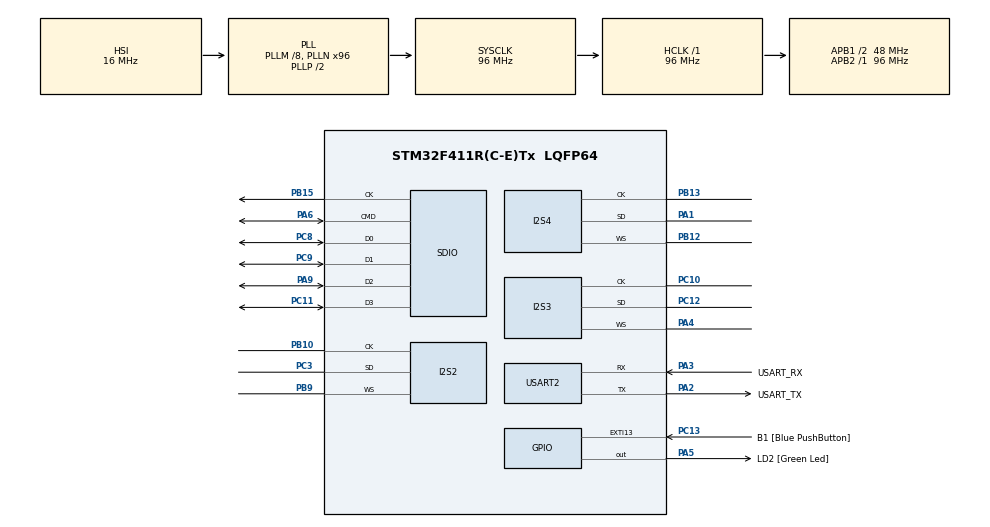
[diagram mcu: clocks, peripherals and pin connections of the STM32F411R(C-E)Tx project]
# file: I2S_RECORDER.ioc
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Dma.Request0=SPI3_RX
Dma.Request1=SPI2_RX
Dma.Request2=SPI4_RX
Dma.SPI2_RX.1.Direction=DMA_PERIPH_TO_MEMORY
Dma.SPI2_RX.1.FIFOMode=DMA_FIFOMODE_DISABLE
Dma.SPI2_RX.1.Instance=DMA1_Stream3
Dma.SPI2_RX.1.MemDataAlignment=DMA_MDATAALIGN_HALFWORD
Dma.SPI2_RX.1.MemInc=DMA_MINC_ENABLE
Dma.SPI2_RX.1.Mode=DMA_CIRCULAR
Dma.SPI2_RX.1.PeriphDataAlignment=DMA_PDATAALIGN_HALFWORD
Dma.SPI2_RX.1.PeriphInc=DMA_PINC_DISABLE
Dma.SPI2_RX.1.Priority=DMA_PRIORITY_LOW
Dma.SPI3_RX.0.Direction=DMA_PERIPH_TO_MEMORY
Dma.SPI3_RX.0.FIFOMode=DMA_FIFOMODE_DISABLE
Dma.SPI3_RX.0.Instance=DMA1_Stream0
Dma.SPI3_RX.0.MemDataAlignment=DMA_MDATAALIGN_HALFWORD
Dma.SPI3_RX.0.MemInc=DMA_MINC_ENABLE
Dma.SPI3_RX.0.Mode=DMA_CIRCULAR
Dma.SPI3_RX.0.PeriphDataAlignment=DMA_PDATAALIGN_HALFWORD
Dma.SPI3_RX.0.PeriphInc=DMA_PINC_DISABLE
Dma.SPI3_RX.0.Priority=DMA_PRIORITY_LOW
Dma.SPI4_RX.2.Direction=DMA_PERIPH_TO_MEMORY
Dma.SPI4_RX.2.FIFOMode=DMA_FIFOMODE_DISABLE
Dma.SPI4_RX.2.Instance=DMA2_Stream0
Dma.SPI4_RX.2.MemDataAlignment=DMA_MDATAALIGN_HALFWORD
Dma.SPI4_RX.2.MemInc=DMA_MINC_ENABLE
Dma.SPI4_RX.2.Mode=DMA_CIRCULAR
Dma.SPI4_RX.2.PeriphDataAlignment=DMA_PDATAALIGN_HALFWORD
Dma.SPI4_RX.2.PeriphInc=DMA_PINC_DISABLE
Dma.SPI4_RX.2.Priority=DMA_PRIORITY_LOW
FATFS._FS_LOCK=3
I2S2.AudioFreq=I2S_AUDIOFREQ_22K
I2S2.DataFormat=I2S_DATAFORMAT_16B_EXTENDED
I2S2.ErrorAudioFreq=0.26 %
I2S2.FullDuplexMode=I2S_FULLDUPLEXMODE_DISABLE
I2S2.Instance=SPI$Index
I2S2.Mode=I2S_MODE_MASTER_RX
I2S2.RealAudioFreq=22.058 KHz
I2S2.VirtualMode=I2S_MODE_MASTER
I2S3.AudioFreq=I2S_AUDIOFREQ_22K
I2S3.DataFormat=I2S_DATAFORMAT_16B_EXTENDED
I2S3.ErrorAudioFreq=0.26 %
I2S3.FullDuplexMode=I2S_FULLDUPLEXMODE_DISABLE
I2S3.Instance=SPI$Index
I2S3.Mode=I2S_MODE_MASTER_RX
I2S3.RealAudioFreq=22.058 KHz
I2S3.VirtualMode=I2S_MODE_MASTER
I2S4.AudioFreq=I2S_AUDIOFREQ_22K
I2S4.DataFormat=I2S_DATAFORMAT_16B_EXTENDED
I2S4.ErrorAudioFreq=0.26 %
I2S4.FullDuplexMode=I2S_FULLDUPLEXMODE_DISABLE
I2S4.Instance=SPI$Index
I2S4.Mode=I2S_MODE_MASTER_RX
I2S4.RealAudioFreq=22.058 KHz
I2S4.VirtualMode=I2S_MODE_MASTER
Mcu.Family=STM32F4
Mcu.Name=STM32F411R(C-E)Tx
Mcu.Package=LQFP64
NVIC.DMA1_Stream0_IRQn=true\:0\:0\:false\:false\:true\:false\:true\:true
NVIC.DMA1_Stream3_IRQn=true\:0\:0\:false\:false\:true\:false\:true\:true
NVIC.DMA2_Stream0_IRQn=true\:0\:0\:false\:false\:true\:false\:true\:true
NVIC.EXTI15_10_IRQn=true\:0\:0\:false\:false\:true\:true\:true\:true
NVIC.PriorityGroup=NVIC_PRIORITYGROUP_0
PA1.Mode=Half_Duplex_Master
PA1.Signal=I2S4_SD
PA13.GPIO_Label=TMS
PA13.Mode=Trace_Asynchronous_SW
PA13.Signal=SYS_JTMS-SWDIO
PA14.GPIO_Label=TCK
PA14.Mode=Trace_Asynchronous_SW
PA14.Signal=SYS_JTCK-SWCLK
PA2.GPIO_Label=USART_TX
PA2.Mode=Asynchronous
PA2.Signal=USART2_TX
PA3.GPIO_Label=USART_RX
PA3.Mode=Asynchronous
PA3.Signal=USART2_RX
PA4.Mode=Half_Duplex_Master
PA4.Signal=I2S3_WS
PA5.GPIO_Label=LD2 [Green Led]
PA5.Signal=GPIO_Output
PA6.GPIO_PuPd=GPIO_PULLUP
PA6.Mode=SD_4_bits_Wide_bus
PA6.Signal=SDIO_CMD
PA9.GPIO_PuPd=GPIO_PULLUP
PA9.Mode=SD_4_bits_Wide_bus
PA9.Signal=SDIO_D2
PB10.Mode=Half_Duplex_Master
PB10.Signal=I2S2_CK
PB12.Mode=Half_Duplex_Master
PB12.Signal=I2S4_WS
PB13.Mode=Half_Duplex_Master
PB13.Signal=I2S4_CK
PB15.GPIO_PuPd=GPIO_PULLUP
PB15.Mode=SD_4_bits_Wide_bus
PB15.Signal=SDIO_CK
PB3.GPIO_Label=SWO
PB3.Mode=Trace_Asynchronous_SW
PB3.Signal=SYS_JTDO-SWO
PB9.Mode=Half_Duplex_Master
PB9.Signal=I2S2_WS
PC10.Mode=Half_Duplex_Master
PC10.Signal=I2S3_CK
PC11.GPIO_PuPd=GPIO_PULLUP
PC11.Mode=SD_4_bits_Wide_bus
PC11.Signal=SDIO_D3
PC12.Mode=Half_Duplex_Master
PC12.Signal=I2S3_SD
PC13-ANTI_TAMP.GPIO_Label=B1 [Blue PushButton]
PC13-ANTI_TAMP.Signal=GPXTI13
PC14-OSC32_IN.Mode=LSE-External-Oscillator
PC14-OSC32_IN.Signal=RCC_OSC32_IN
PC15-OSC32_OUT.Mode=LSE-External-Oscillator
PC15-OSC32_OUT.Signal=RCC_OSC32_OUT
PC3.Mode=Half_Duplex_Master
PC3.Signal=I2S2_SD
PC8.GPIO_PuPd=GPIO_PULLUP
PC8.Mode=SD_4_bits_Wide_bus
PC8.Signal=SDIO_D0
PC9.GPIO_PuPd=GPIO_PULLUP
PC9.Mode=SD_4_bits_Wide_bus
PC9.Signal=SDIO_D1
PH0\ -\ OSC_IN.Mode=HSE-External-Clock-Source
PH0\ -\ OSC_IN.Signal=RCC_OSC_IN
PH1\ -\ OSC_OUT.Mode=HSE-External-Clock-Source
PH1\ -\ OSC_OUT.Signal=RCC_OSC_OUT
ProjectManager.HeapSize=0x200
ProjectManager.StackSize=0x400
ProjectManager.TargetToolchain=STM32CubeIDE
RCC.48MHZClocksFreq_Value=48000000
RCC.AHBFreq_Value=96000000
RCC.APB1CLKDivider=RCC_HCLK_DIV2
RCC.APB1Freq_Value=48000000
RCC.APB1TimFreq_Value=96000000
RCC.APB2Freq_Value=96000000
RCC.APB2TimFreq_Value=96000000
RCC.CortexFreq_Value=96000000
RCC.FLatency-AdvancedSettings=FLASH_LATENCY_3
RCC.HCLKFreq_Value=96000000
RCC.HSE_VALUE=8000000
RCC.HSI_VALUE=16000000
RCC.PLLM=8
RCC.PLLN=96
RCC.SYSCLKFreq_VALUE=96000000
RCC.SYSCLKSource=RCC_SYSCLKSOURCE_PLLCLK
RCC.VCOOutputFreq_Value=192000000
SDIO.ClockDiv=12
USART2.VirtualMode=VM_ASYNC
VP_FATFS_VS_SDIO.Mode=SDIO
board=NUCLEO-F411RE

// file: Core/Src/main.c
/* USER CODE BEGIN Header */
/**
  ******************************************************************************
  * @file           : main.c
  * @brief          : Main program body
  ******************************************************************************
  * @attention
  *
  * Copyright (c) 2023 STMicroelectronics.
  * All rights reserved.
  *
  * This software is licensed under terms that can be found in the LICENSE file
  * in the root directory of this software component.
  * If no LICENSE file comes with this software, it is provided AS-IS.
  *
  ******************************************************************************
  */
/* USER CODE END Header */
#include "main.h"
#include "fatfs.h"

/* USER CODE BEGIN Includes */
#include "stdio.h"
#include "audio_sd.h"
#include "File_Handling.h"
/* USER CODE END Includes */

/* USER CODE BEGIN PD */
#define WAV_WRITE_SAMPLE_COUNT 2048
/* USER CODE END PD */

 I2S_HandleTypeDef hi2s2;
I2S_HandleTypeDef hi2s3;
I2S_HandleTypeDef hi2s4;
DMA_HandleTypeDef hdma_spi2_rx;
DMA_HandleTypeDef hdma_spi3_rx;
DMA_HandleTypeDef hdma_spi4_rx;

SD_HandleTypeDef hsd;

UART_HandleTypeDef huart2;

/* USER CODE BEGIN PV */

volatile uint8_t button_flag, start_stop_recording;

int16_t data_i2s1[WAV_WRITE_SAMPLE_COUNT];
int16_t data_i2s2[WAV_WRITE_SAMPLE_COUNT];
int16_t data_i2s3[WAV_WRITE_SAMPLE_COUNT];

volatile int16_t sample_i2s1;
volatile int16_t sample_i2s2;
volatile int16_t sample_i2s3;

volatile uint8_t  half_i2s1, full_i2s1;
volatile uint8_t  half_i2s2, full_i2s2;
volatile uint8_t  half_i2s3, full_i2s3;

/* USER CODE END PV */

void SystemClock_Config(void);
void PeriphCommonClock_Config(void);
static void MX_GPIO_Init(void);
static void MX_DMA_Init(void);
static void MX_USART2_UART_Init(void);
static void MX_SDIO_SD_Init(void);
static void MX_I2S3_Init(void);
static void MX_I2S2_Init(void);
static void MX_I2S4_Init(void);

/* USER CODE BEGIN 0 */
char buffer[100];
int indx = 0;
/* USER CODE END 0 */

int main(void)
{

  /* MCU Configuration--------------------------------------------------------*/

  /* Reset of all peripherals, Initializes the Flash interface and the Systick. */
  HAL_Init();

  /* Configure the system clock */
  SystemClock_Config();

/* Configure the peripherals common clocks */
  PeriphCommonClock_Config();

  /* Initialize all configured peripherals */
  MX_GPIO_Init();
  MX_DMA_Init();
  MX_USART2_UART_Init();
  MX_FATFS_Init();
  MX_SDIO_SD_Init();
  MX_I2S3_Init();
  MX_I2S2_Init();
  MX_I2S4_Init();
  /* USER CODE BEGIN 2 */
  HAL_I2S_DMAStop(&hi2s2);
  //HAL_I2S_Receive_DMA(&hi2s2, (uint16_t *)data_i2s, sizeof(data_i2s)/2);
  HAL_Delay(500);
  sd_card_init();

	// HAL_I2S_Receive_DMA(&hi2s2, (uint8_t*)data_i2s, sizeof(data_i2s)/2);
	// Mount_SD("/");
	// Format_SD();
	// Create_File("FILE1.TXT");
	// Update_File("FILE1.TXT", "test");
	// Create_File("FILE2.TXT");
	// Unmount_SD("/");

  /* USER CODE END 2 */

  /* Infinite loop */
  /* USER CODE BEGIN WHILE */
  while (1)
  {
	  if(button_flag)
		  {

			  if(start_stop_recording)
			  {
				  HAL_I2S_DMAStop(&hi2s2);
				  HAL_I2S_DMAStop(&hi2s3);
				  HAL_I2S_DMAStop(&hi2s4);
				  start_stop_recording = 0;
				  stop_recording();
				  half_i2s1 = 0;
				  full_i2s1 = 0;
				  half_i2s2 = 0;
				  full_i2s2 = 0;
				  half_i2s3 = 0;
				  full_i2s3 = 0;
				  printf("stop recording \n");
			  }
			  else
			  {
				  start_stop_recording = 1;
				  start_recording(I2S_AUDIOFREQ_22K);
				  //printf("start_recording %d and %d\n", half_i2s, full_i2s,1);
				  HAL_I2S_Receive_DMA(&hi2s2, (uint16_t *)data_i2s1, sizeof(data_i2s1)/2);
				  HAL_I2S_Receive_DMA(&hi2s3, (uint16_t *)data_i2s2, sizeof(data_i2s2)/2);
				  HAL_I2S_Receive_DMA(&hi2s4, (uint16_t *)data_i2s3, sizeof(data_i2s3)/2);

			  }
			  button_flag = 0;
		  }
    /* USER CODE END WHILE */

    /* USER CODE BEGIN 3 */
	  //recording channel 1
	  if(start_stop_recording == 1 && half_i2s1 == 1)
	  {
		  write2wave_file(((uint8_t*)data_i2s1),	 WAV_WRITE_SAMPLE_COUNT,1);
		  half_i2s1 = 0;
	  }
	  if(start_stop_recording == 1 && full_i2s1 == 1)
	  {
		  write2wave_file(((uint8_t*)data_i2s1) + WAV_WRITE_SAMPLE_COUNT, WAV_WRITE_SAMPLE_COUNT,1);
		  full_i2s1 = 0;
	  }

	  //recording channel 2
	  if(start_stop_recording == 1 && half_i2s2 == 1)
	  {
		  write2wave_file(((uint8_t*)data_i2s2),	 WAV_WRITE_SAMPLE_COUNT,2);
		  half_i2s2 = 0;
	  }
	  if(start_stop_recording == 1 && full_i2s2 == 1)
	  {
		  write2wave_file(((uint8_t*)data_i2s2) + WAV_WRITE_SAMPLE_COUNT, WAV_WRITE_SAMPLE_COUNT,2);
		  full_i2s2 = 0;
	  }

	  //recording channel 3
	  if(start_stop_recording == 1 && half_i2s3 == 1)
	  {
		  write2wave_file(((uint8_t*)data_i2s3),	 WAV_WRITE_SAMPLE_COUNT,3);
		  half_i2s3 = 0;
	  }
	  if(start_stop_recording == 1 && full_i2s3 == 1)
	  {
		  write2wave_file(((uint8_t*)data_i2s3) + WAV_WRITE_SAMPLE_COUNT, WAV_WRITE_SAMPLE_COUNT,3);
		  full_i2s3 = 0;
	  }

  }
  /* USER CODE END 3 */
}

void SystemClock_Config(void)
{
  RCC_OscInitTypeDef RCC_OscInitStruct = {0};
  RCC_ClkInitTypeDef RCC_ClkInitStruct = {0};

  /** Configure the main internal regulator output voltage
  */
  __HAL_RCC_PWR_CLK_ENABLE();
  __HAL_PWR_VOLTAGESCALING_CONFIG(PWR_REGULATOR_VOLTAGE_SCALE1);

  /** Initializes the RCC Oscillators according to the specified parameters
  * in the RCC_OscInitTypeDef structure.
  */
  RCC_OscInitStruct.OscillatorType = RCC_OSCILLATORTYPE_HSI;
  RCC_OscInitStruct.HSIState = RCC_HSI_ON;
  RCC_OscInitStruct.HSICalibrationValue = RCC_HSICALIBRATION_DEFAULT;
  RCC_OscInitStruct.PLL.PLLState = RCC_PLL_ON;
  RCC_OscInitStruct.PLL.PLLSource = RCC_PLLSOURCE_HSI;
  RCC_OscInitStruct.PLL.PLLM = 8;
  RCC_OscInitStruct.PLL.PLLN = 96;
  RCC_OscInitStruct.PLL.PLLP = RCC_PLLP_DIV2;
  RCC_OscInitStruct.PLL.PLLQ = 4;
  if (HAL_RCC_OscConfig(&RCC_OscInitStruct) != HAL_OK)
  {
    Error_Handler();
  }

  /** Initializes the CPU, AHB and APB buses clocks
  */
  RCC_ClkInitStruct.ClockType = RCC_CLOCKTYPE_HCLK|RCC_CLOCKTYPE_SYSCLK
                              |RCC_CLOCKTYPE_PCLK1|RCC_CLOCKTYPE_PCLK2;
  RCC_ClkInitStruct.SYSCLKSource = RCC_SYSCLKSOURCE_PLLCLK;
  RCC_ClkInitStruct.AHBCLKDivider = RCC_SYSCLK_DIV1;
  RCC_ClkInitStruct.APB1CLKDivider = RCC_HCLK_DIV2;
  RCC_ClkInitStruct.APB2CLKDivider = RCC_HCLK_DIV1;

  if (HAL_RCC_ClockConfig(&RCC_ClkInitStruct, FLASH_LATENCY_3) != HAL_OK)
  {
    Error_Handler();
  }
}

void PeriphCommonClock_Config(void)
{
  RCC_PeriphCLKInitTypeDef PeriphClkInitStruct = {0};

  /** Initializes the peripherals clock
  */
  PeriphClkInitStruct.PeriphClockSelection = RCC_PERIPHCLK_I2S;
  PeriphClkInitStruct.PLLI2S.PLLI2SN = 192;
  PeriphClkInitStruct.PLLI2S.PLLI2SM = 16;
  PeriphClkInitStruct.PLLI2S.PLLI2SR = 2;
  if (HAL_RCCEx_PeriphCLKConfig(&PeriphClkInitStruct) != HAL_OK)
  {
    Error_Handler();
  }
}

static void MX_I2S2_Init(void)
{

  hi2s2.Instance = SPI2;
  hi2s2.Init.Mode = I2S_MODE_MASTER_RX;
  hi2s2.Init.Standard = I2S_STANDARD_PHILIPS;
  hi2s2.Init.DataFormat = I2S_DATAFORMAT_16B_EXTENDED;
  hi2s2.Init.MCLKOutput = I2S_MCLKOUTPUT_DISABLE;
  hi2s2.Init.AudioFreq = I2S_AUDIOFREQ_22K;
  hi2s2.Init.CPOL = I2S_CPOL_LOW;
  hi2s2.Init.ClockSource = I2S_CLOCK_PLL;
  hi2s2.Init.FullDuplexMode = I2S_FULLDUPLEXMODE_DISABLE;
  if (HAL_I2S_Init(&hi2s2) != HAL_OK)
  {
    Error_Handler();
  }

}

static void MX_I2S3_Init(void)
{

  hi2s3.Instance = SPI3;
  hi2s3.Init.Mode = I2S_MODE_MASTER_RX;
  hi2s3.Init.Standard = I2S_STANDARD_PHILIPS;
  hi2s3.Init.DataFormat = I2S_DATAFORMAT_16B_EXTENDED;
  hi2s3.Init.MCLKOutput = I2S_MCLKOUTPUT_DISABLE;
  hi2s3.Init.AudioFreq = I2S_AUDIOFREQ_22K;
  hi2s3.Init.CPOL = I2S_CPOL_LOW;
  hi2s3.Init.ClockSource = I2S_CLOCK_PLL;
  hi2s3.Init.FullDuplexMode = I2S_FULLDUPLEXMODE_DISABLE;
  if (HAL_I2S_Init(&hi2s3) != HAL_OK)
  {
    Error_Handler();
  }

}

static void MX_I2S4_Init(void)
{

  hi2s4.Instance = SPI4;
  hi2s4.Init.Mode = I2S_MODE_MASTER_RX;
  hi2s4.Init.Standard = I2S_STANDARD_PHILIPS;
  hi2s4.Init.DataFormat = I2S_DATAFORMAT_16B_EXTENDED;
  hi2s4.Init.MCLKOutput = I2S_MCLKOUTPUT_DISABLE;
  hi2s4.Init.AudioFreq = I2S_AUDIOFREQ_22K;
  hi2s4.Init.CPOL = I2S_CPOL_LOW;
  hi2s4.Init.ClockSource = I2S_CLOCK_PLL;
  hi2s4.Init.FullDuplexMode = I2S_FULLDUPLEXMODE_DISABLE;
  if (HAL_I2S_Init(&hi2s4) != HAL_OK)
  {
    Error_Handler();
  }

}

static void MX_SDIO_SD_Init(void)
{

  hsd.Instance = SDIO;
  hsd.Init.ClockEdge = SDIO_CLOCK_EDGE_RISING;
  hsd.Init.ClockBypass = SDIO_CLOCK_BYPASS_DISABLE;
  hsd.Init.ClockPowerSave = SDIO_CLOCK_POWER_SAVE_DISABLE;
  hsd.Init.BusWide = SDIO_BUS_WIDE_1B;
  hsd.Init.HardwareFlowControl = SDIO_HARDWARE_FLOW_CONTROL_ENABLE;
  hsd.Init.ClockDiv = 12;

}

static void MX_USART2_UART_Init(void)
{

  huart2.Instance = USART2;
  huart2.Init.BaudRate = 115200;
  huart2.Init.WordLength = UART_WORDLENGTH_8B;
  huart2.Init.StopBits = UART_STOPBITS_1;
  huart2.Init.Parity = UART_PARITY_NONE;
  huart2.Init.Mode = UART_MODE_TX_RX;
  huart2.Init.HwFlowCtl = UART_HWCONTROL_NONE;
  huart2.Init.OverSampling = UART_OVERSAMPLING_16;
  if (HAL_UART_Init(&huart2) != HAL_OK)
  {
    Error_Handler();
  }

}

static void MX_DMA_Init(void)
{

  /* DMA controller clock enable */
  __HAL_RCC_DMA1_CLK_ENABLE();
  __HAL_RCC_DMA2_CLK_ENABLE();

  /* DMA interrupt init */
  /* DMA1_Stream0_IRQn interrupt configuration */
  HAL_NVIC_SetPriority(DMA1_Stream0_IRQn, 0, 0);
  HAL_NVIC_EnableIRQ(DMA1_Stream0_IRQn);
  /* DMA1_Stream3_IRQn interrupt configuration */
  HAL_NVIC_SetPriority(DMA1_Stream3_IRQn, 0, 0);
  HAL_NVIC_EnableIRQ(DMA1_Stream3_IRQn);
  /* DMA2_Stream0_IRQn interrupt configuration */
  HAL_NVIC_SetPriority(DMA2_Stream0_IRQn, 0, 0);
  HAL_NVIC_EnableIRQ(DMA2_Stream0_IRQn);

}

static void MX_GPIO_Init(void)
{
  GPIO_InitTypeDef GPIO_InitStruct = {0};

  /* GPIO Ports Clock Enable */
  __HAL_RCC_GPIOC_CLK_ENABLE();
  __HAL_RCC_GPIOH_CLK_ENABLE();
  __HAL_RCC_GPIOA_CLK_ENABLE();
  __HAL_RCC_GPIOB_CLK_ENABLE();

  /*Configure GPIO pin Output Level */
  HAL_GPIO_WritePin(GPIOA, LD2_Pin|LED_init_Pin, GPIO_PIN_RESET);

  /*Configure GPIO pin Output Level */
  HAL_GPIO_WritePin(LED_write_GPIO_Port, LED_write_Pin, GPIO_PIN_RESET);

  /*Configure GPIO pin : B1_Pin */
  GPIO_InitStruct.Pin = B1_Pin;
  GPIO_InitStruct.Mode = GPIO_MODE_IT_RISING;
  GPIO_InitStruct.Pull = GPIO_NOPULL;
  HAL_GPIO_Init(B1_GPIO_Port, &GPIO_InitStruct);

  /*Configure GPIO pins : LD2_Pin LED_init_Pin */
  GPIO_InitStruct.Pin = LD2_Pin|LED_init_Pin;
  GPIO_InitStruct.Mode = GPIO_MODE_OUTPUT_PP;
  GPIO_InitStruct.Pull = GPIO_NOPULL;
  GPIO_InitStruct.Speed = GPIO_SPEED_FREQ_LOW;
  HAL_GPIO_Init(GPIOA, &GPIO_InitStruct);

  /*Configure GPIO pin : LED_write_Pin */
  GPIO_InitStruct.Pin = LED_write_Pin;
  GPIO_InitStruct.Mode = GPIO_MODE_OUTPUT_PP;
  GPIO_InitStruct.Pull = GPIO_NOPULL;
  GPIO_InitStruct.Speed = GPIO_SPEED_FREQ_LOW;
  HAL_GPIO_Init(LED_write_GPIO_Port, &GPIO_InitStruct);

  /* EXTI interrupt init*/
  HAL_NVIC_SetPriority(EXTI15_10_IRQn, 0, 0);
  HAL_NVIC_EnableIRQ(EXTI15_10_IRQn);

}

/* USER CODE BEGIN 4 */
int _write(int file, char *ptr, int len)
{
  int DataIdx;
  for (DataIdx = 0; DataIdx < len; DataIdx++)
  {
    ITM_SendChar(*ptr++);
  }
  return len;
}

//	l,r,l,r,l,
void HAL_I2S_RxCpltCallback(I2S_HandleTypeDef *hi2s)
{
	if(hi2s->Instance == hi2s2.Instance)
	{
		full_i2s1 = 1;
	}
	else if(hi2s->Instance == hi2s3.Instance)
	{
		full_i2s2 = 1;
	}
	else if(hi2s->Instance == hi2s4.Instance)
	{
		full_i2s3 = 1;
	}

}

void HAL_I2S_RxHalfCpltCallback(I2S_HandleTypeDef *hi2s)
{
	if(hi2s->Instance == hi2s2.Instance)
	{
		half_i2s1 = 1;
	}
	else if(hi2s->Instance == hi2s3.Instance)
	{
		half_i2s2 = 1;
	}
	else if(hi2s->Instance == hi2s4.Instance)
	{
		half_i2s3 = 1;
	}
}

void HAL_GPIO_EXTI_Callback(uint16_t GPIO_Pin)
{
	if(GPIO_Pin == B1_Pin)
	{
		button_flag = 1;
	}
}

/* USER CODE END 4 */

void Error_Handler(void)
{
  __disable_irq();
  while (1)
  {
  }
}
